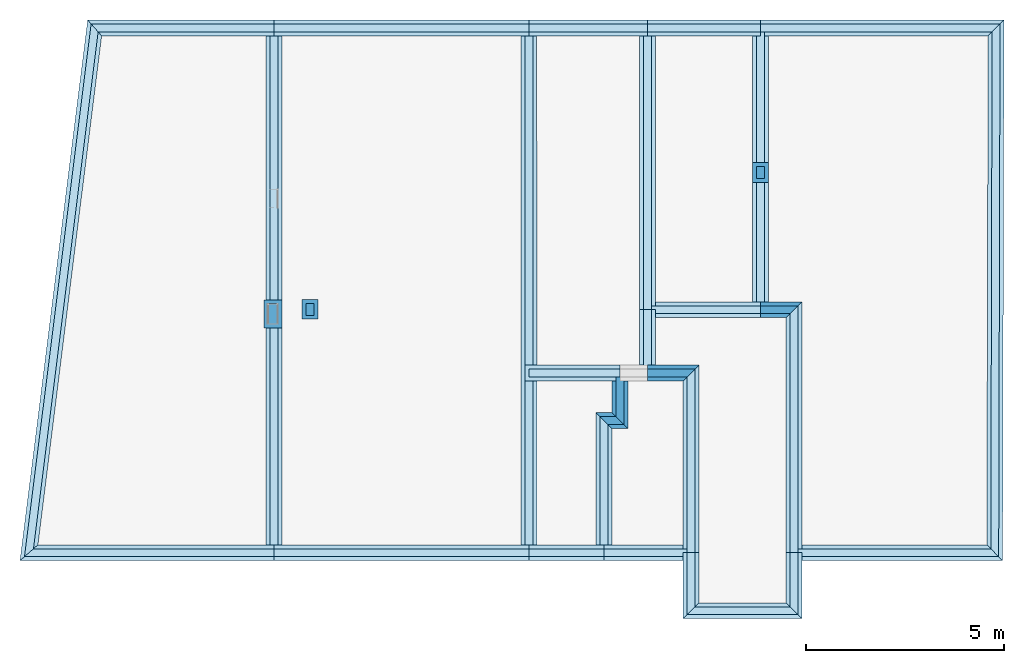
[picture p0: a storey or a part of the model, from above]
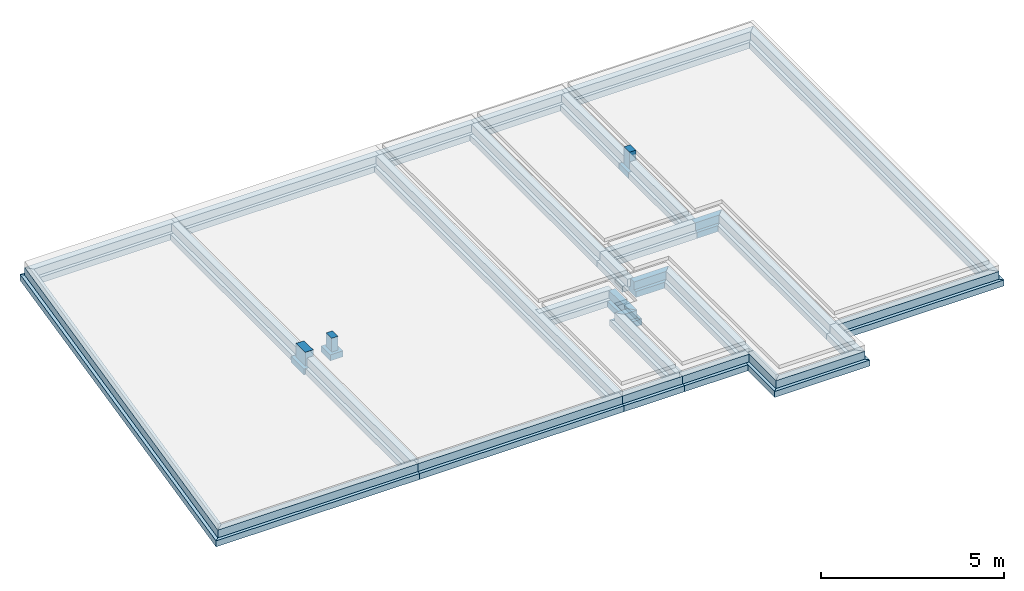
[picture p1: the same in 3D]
Properties of the parts of a building model (IFC2X3)

# File
Description: ISANGARD maison de santé et 9 logements, ViewDefinition [CoordinationView]
File name: G:\2023 Freyssinet\2023_MEC\00_Projet\23 24_04_ISANGARD\ISANGARD.IFC
Time: 2024-03-13T08:15:07
Author: Utilisateur par défaut
Written by: 2023-A
Made in: ATTIC+ Classic-Pack / Graphic-Pack Export_IFC 2023-A
Authorization: Personnes autorisées

# IfcProject, ISANGARD maison de santé et 9 logements
Description: ISANGARD maison de santé et 9 logements; Phase: EXE GROS OEUVRE ISANGARD

# IfcSite
RefLatitude: 0, 0, 0; RefLongitude: 0, 0, 0; RefElevation: 0 m

# IfcBuilding, Classeur ENS Ensemble
LongName: Classeur ENS Ensemble

# IfcBuildingStorey (5)
In: Classeur ENS Ensemble
Name | Description = LongName | Elevation (m)
000 Fondations | 000 Fondations | 0
001 RdC | 001 RdC | 0
002 R+1 | 002 R+1 | 3.3
003 R+2 | 003 R+2 | 6.03
004 Toiture Terrasse | 004 Toiture Terrasse | 8.73

# IfcBeam (184)
Type - PredefinedType: BEAM
Material: Default material
Name | In | Description | GrossVolume (m3) | NominalLength (m) | CrossSectionArea (m2) | OuterSurfaceArea (m2) | TotalSurfaceArea (m2)
3 x poutre fictive -32 | 000 Fondations | poutre fictive -32 | 0 | 0.15 | 0 | 0 | 0
7 x poutre fictive -32 | 000 Fondations | poutre fictive -32 | 0 | 0.1 | 0 | 0 | 0
poutre fictive -32 | 000 Fondations | poutre fictive -32 | 0 | 0.45 | 0 | 0 | 0
2 x poutre fictive -32 | 000 Fondations | poutre fictive -32 | 0 | 0.5 | 0 | 0 | 0
poutre fictive -32 | 000 Fondations | poutre fictive -32 | 0 | 0.0198567 | 0 | 0 | 0
poutre BA | 001 RdC | poutre BA | 0.390044 | 4.87555 | 0.08 | 1.95022 | 5.93066
poutre BA | 001 RdC | poutre BA | 0.00347491 | 0.0198567 | 0.175 | 0.0138997 | 0.212728
poutre BA | 001 RdC | poutre BA | 0.40425 | 2.31 | 0.175 | 1.617 | 4.494
poutre BA | 001 RdC | poutre BA | 0.22925 | 1.31 | 0.175 | 0.917 | 2.5765
poutre BA | 001 RdC | poutre BA | 0.28043 | 1.60246 | 0.175 | 1.12172 | 3.14951
poutre BA | 001 RdC | poutre BA | 0.133803 | 1.07043 | 0.125 | 0.535213 | 1.73064
poutre BA | 001 RdC | poutre BA | 0.22505 | 3.215 | 0.07 | 1.12525 | 3.6065
poutre BA | 001 RdC | poutre BA | 0.23835 | 3.405 | 0.07 | 1.19175 | 3.8155
poutre fictive | 001 RdC | poutre fictive | 0 | 0.075 | 0 | 0 | 0
poutre fictive | 001 RdC | poutre fictive | 0 | 0.125 | 0 | 0 | 0
poutre BA | 001 RdC | poutre BA | 0.21615 | 1.23514 | 0.175 | 0.8646 | 2.43427
poutre fictive | 001 RdC | poutre fictive | 0 | 0.63277 | 0 | 0 | 0
poutre fictive | 001 RdC | poutre fictive | 0 | 1.4652 | 0 | 0 | 0
poutre fictive | 001 RdC | poutre fictive | 0 | 5.06775 | 0 | 0 | 0
poutre fictive | 001 RdC | poutre fictive | 0 | 1.465 | 0 | 0 | 0
poutre fictive | 001 RdC | poutre fictive | 0 | 5.07148 | 0 | 0 | 0
poutre fictive | 001 RdC | poutre fictive | 0 | 0.1 | 0 | 0 | 0
poutre BA | 001 RdC | poutre BA | 0.004 | 0.1 | 0.04 | 0.02 | 0.12
poutre fictive | 001 RdC | poutre fictive | 0 | 0.124967 | 0 | 0 | 0
poutre fictive 285 | 001 RdC | poutre fictive 285 | 0 | 0.00999994 | 0 | 0 | 0
2 x poutre fictive 285 | 001 RdC | poutre fictive 285 | 0 | 0.12 | 0 | 0 | 0
Poutre auto | 001 RdC | Poutre auto | 0 | 5.88381 | 0 | 1.17676 | 2.35352
poutre BA | 001 RdC | poutre BA | 0.458125 | 3.665 | 0.125 | 1.8325 | 5.6225
poutre BA | 001 RdC | poutre BA | 0.0151187 | 0.120949 | 0.125 | 0.0604747 | 0.256424
poutre BA | 001 RdC | poutre BA | 0.140622 | 1.56247 | 0.09 | 0.70311 | 2.12121
poutre BA | 001 RdC | poutre BA | 0.009 | 0.1 | 0.09 | 0.045 | 0.22
poutre fictive 285 | 001 RdC | poutre fictive 285 | 0 | 0.1 | 0 | 0 | 0
poutre BA | 001 RdC | poutre BA | 0.0125 | 0.1 | 0.125 | 0.05 | 0.225
poutre BA | 001 RdC | poutre BA | 0.246601 | 2.74002 | 0.09 | 1.23301 | 3.65202
poutre BA | 001 RdC | poutre BA | 0.00000147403 | 0.249984 | 0.09 | 0.00000737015 | 0.190008
poutre BA | 001 RdC | poutre BA | 0.064 | 1.6 | 0.04 | 0.32 | 1.32
poutre fictive 310 | 001 RdC | poutre fictive 310 | 0 | 2.83619 | 0 | 0 | 0
poutre BA | 001 RdC | poutre BA | 0.048 | 1.2 | 0.04 | 0.24 | 1
poutre fictive 310 | 001 RdC | poutre fictive 310 | 0 | 4.34 | 0 | 0 | 0
Bande noyée 20 x 20 | 001 RdC | Bande noyée 20 x 20 | 0.0445201 | 1.113 | 0.04 | 0.222601 | 0.930403
poutre BA | 001 RdC | poutre BA | 0.68775 | 3.93 | 0.175 | 2.751 | 7.572
poutre BA | 001 RdC | poutre BA | 0.687751 | 3.93001 | 0.175 | 2.751 | 7.57217
poutre BA rive balcon | 001 RdC | poutre BA rive balcon | 0.105063 | 1.40084 | 0.075 | 0.700422 | 1.8961
poutre BA rive balcon | 001 RdC | poutre BA rive balcon | 0.00566888 | 0.0755851 | 0.075 | 0.0377926 | 0.182647
poutre BA rive balcon | 001 RdC | poutre BA rive balcon | 0.197344 | 2.63125 | 0.075 | 1.31563 | 3.49563
poutre BA rive balcon | 001 RdC | poutre BA rive balcon | 0.335239 | 4.46986 | 0.075 | 2.23493 | 5.88582
poutre fictive 290 | 001 RdC | poutre fictive 290 | 0 | 1.415 | 0 | 0 | 0
poutre fictive 290 | 001 RdC | poutre fictive 290 | 0 | 0.075 | 0 | 0 | 0
poutre fictive 290 | 001 RdC | poutre fictive 290 | 0 | 1.49 | 0 | 0 | 0
2 x poutre fictive 306 | 001 RdC | poutre fictive 306 | 0 | 0.075 | 0 | 0 | 0
3 x poutre fictive 306 | 001 RdC | poutre fictive 306 | 0 | 0.0755851 | 0 | 0 | 0
poutre fictive 306 | 001 RdC | poutre fictive 306 | 0 | 0.1 | 0 | 0 | 0
poutre BA rive balcon | 001 RdC | poutre BA rive balcon | 0.177301 | 2.36401 | 0.075 | 1.182 | 3.14821
poutre fictive 306 | 001 RdC | poutre fictive 306 | 0 | 4.82129 | 0 | 0 | 0
poutre fictive 306 | 001 RdC | poutre fictive 306 | 0 | 4.98587 | 0 | 0 | 0
poutre fictive 306 | 001 RdC | poutre fictive 306 | 0 | 1.315 | 0 | 0 | 0
poutre fictive 306 | 001 RdC | poutre fictive 306 | 0 | 1.32526 | 0 | 0 | 0
4 x poutre fictive 305 | 001 RdC | poutre fictive 305 | 0 | 0.1 | 0 | 0 | 0
2 x poutre fictive 305 | 001 RdC | poutre fictive 305 | 0 | 1.265 | 0 | 0 | 0
2 x poutre fictive 305 | 001 RdC | poutre fictive 305 | 0 | 0.2 | 0 | 0 | 0
poutre fictive 305 | 001 RdC | poutre fictive 305 | 0 | 0.360863 | 0 | 0 | 0
2 x poutre fictive 305 | 001 RdC | poutre fictive 305 | 0 | 6.74 | 0 | 0 | 0
poutre BA 20 x 40 | 001 RdC | poutre BA 20 x 40 | 1.18408e-10 | 0.2 | 0.08 | 5.92039e-10 | 0.32
poutre BA 20 x 40 | 001 RdC | poutre BA 20 x 40 | 0.192 | 2.4 | 0.08 | 0.96 | 3.12
poutre fictive 290 | 001 RdC | poutre fictive 290 | 0 | 0.2 | 0 | 0 | 0
poutre BA rive balcon | 001 RdC | poutre BA rive balcon | 0.122625 | 2.725 | 0.045 | 0.8175 | 2.4975
poutre BA rive balcon | 001 RdC | poutre BA rive balcon | 0.06705 | 1.49 | 0.045 | 0.447 | 1.386
poutre voile BA 20 cm | 002 R+1 | poutre voile BA 20 cm | 0.0337622 | 0.0566479 | 0.596 | 0.168811 | 0.956281
poutre voile BA 20 cm | 002 R+1 | poutre voile BA 20 cm | 0.94168 | 1.58 | 0.596 | 4.7084 | 10.0488
poutre voile BA 20 cm | 002 R+1 | poutre voile BA 20 cm | 0.75394 | 1.265 | 0.596 | 3.7697 | 9.8334
poutre voile BA 20 cm | 002 R+1 | poutre voile BA 20 cm | 3.44488 | 5.78 | 0.596 | 17.2244 | 38.2508
2 x poutre voile BA 20 cm | 002 R+1 | poutre voile BA 20 cm | 0.74129 | 1.265 | 0.586 | 3.70645 | 8.5049
poutre fictive 250 | 002 R+1 | poutre fictive 250 | 0 | 2.96294 | 0 | 0 | 0
poutre voile BA 20 cm | 002 R+1 | poutre voile BA 20 cm | 0.931731 | 1.56331 | 0.596 | 4.65865 | 10.5386
poutre voile BA 20 cm | 002 R+1 | poutre voile BA 20 cm | 1.54016 | 2.58416 | 0.596 | 7.70079 | 16.6588
poutre BA 20 x 48 | 002 R+1 | poutre BA 20 x 48 | 0.264359 | 2.75374 | 0.096 | 1.32179 | 3.84108
poutre BA 20 x 35 | 002 R+1 | poutre BA 20 x 35 | 0.319936 | 4.57052 | 0.07 | 1.59968 | 5.09757
poutre BA 20 x 35 | 002 R+1 | poutre BA 20 x 35 | 0.4963 | 7.09 | 0.07 | 2.4815 | 7.869
poutre BA 20 x 35 | 002 R+1 | poutre BA 20 x 35 | 0.014 | 0.2 | 0.07 | 0.07 | 0.29
2 x poutre fictive 250 | 002 R+1 | poutre fictive 250 | 0 | 1.5 | 0 | 0 | 0
2 x poutre fictive 250 | 002 R+1 | poutre fictive 250 | 0 | 1.70004 | 0 | 0 | 0
poutre BA 20 x 35 | 002 R+1 | poutre BA 20 x 35 | 0.253875 | 3.62678 | 0.07 | 1.26937 | 4.05946
poutre fictive 250 | 002 R+1 | poutre fictive 250 | 0 | 5.44 | 0 | 0 | 0
poutre fictive 250 | 002 R+1 | poutre fictive 250 | 0 | 3.94 | 0 | 0 | 0
poutre fictive 250 | 002 R+1 | poutre fictive 250 | 0 | 1.6 | 0 | 0 | 0
poutre fictive 250 | 002 R+1 | poutre fictive 250 | 0 | 4.78032 | 0 | 0 | 0
poutre fictive 250 | 002 R+1 | poutre fictive 250 | 0 | 2.86496 | 0 | 0 | 0
poutre fictive 250 | 002 R+1 | poutre fictive 250 | 0 | 2.84982 | 0 | 0 | 0
poutre BA 25 x 45 | 002 R+1 | poutre BA 25 x 45 | 0.211495 | 1.87996 | 0.1125 | 0.84598 | 2.74444
poutre fictive 250 | 002 R+1 | poutre fictive 250 | 0 | 2.00327 | 0 | 0 | 0
poutre BA 25 x 45 | 002 R+1 | poutre BA 25 x 45 | 0.0225 | 0.2 | 0.1125 | 0.09 | 0.3925
poutre BA 25 x 45 | 002 R+1 | poutre BA 25 x 45 | 0.385874 | 3.42999 | 0.1125 | 1.5435 | 4.91449
poutre BA 25 x 50 | 002 R+1 | poutre BA 25 x 50 | 0.131636 | 1.05309 | 0.125 | 0.526545 | 1.70464
poutre fictive 250 | 002 R+1 | poutre fictive 250 | 0 | 2.05496 | 0 | 0 | 0
poutre BA 25 x 50 | 002 R+1 | poutre BA 25 x 50 | 0.27441 | 3.92014 | 0.07 | 1.37205 | 4.38216
BN 23 | 002 R+1 | BN 23 | 0.0799049 | 1.73706 | 0.046 | 0.399525 | 1.53987
poutre fictive 250 | 002 R+1 | poutre fictive 250 | 0 | 2.5404 | 0 | 0 | 0
poutre fictive 250 | 002 R+1 | poutre fictive 250 | 0 | 2.25496 | 0 | 0 | 0
2 x poutre fictive 250 | 002 R+1 | poutre fictive 250 | 0 | 0.324552 | 0 | 0 | 0
poutre fictive 250 | 002 R+1 | poutre fictive 250 | 0 | 0.239541 | 0 | 0 | 0
poutre BA 25 x 45 | 002 R+1 | poutre BA 25 x 45 | 0.13613 | 1.21004 | 0.1125 | 0.544519 | 1.80656
poutre fictive 250 | 002 R+1 | poutre fictive 250 | 0 | 2.20308 | 0 | 0 | 0
poutre fictive 250 | 002 R+1 | poutre fictive 250 | 0 | 2.61028 | 0 | 0 | 0
BN 23 | 002 R+1 | BN 23 | 0.0571584 | 1.24257 | 0.046 | 0.285792 | 1.11461
poutre BA 25 x 50 | 002 R+1 | poutre BA 25 x 50 | 0.0249971 | 0.199977 | 0.125 | 0.0999883 | 0.424965
poutre BA 25 x 50 | 002 R+1 | poutre BA 25 x 50 | 0.454262 | 3.6341 | 0.125 | 1.81705 | 5.57615
poutre voile BA 20 cm | 002 R+1 | poutre voile BA 20 cm | 0.155142 | 0.260305 | 0.596 | 0.77571 | 2.25154
Poutre auto | 002 R+1 | Poutre auto | 0 | 5.3 | 0 | 1.219 | 2.438
BN 23 | 002 R+1 | BN 23 | 0.0716416 | 1.55743 | 0.046 | 0.358208 | 1.38539
poutre fictive 250 | 002 R+1 | poutre fictive 250 | 0 | 1.50225 | 0 | 0 | 0
poutre voile BA 20 cm | 002 R+1 | poutre voile BA 20 cm | 0.0260932 | 0.0437805 | 0.596 | 0.130466 | 0.874444
BN 23 | 002 R+1 | BN 23 | 0.0599095 | 1.30238 | 0.046 | 0.299547 | 1.16605
poutre voile BA 20 cm | 002 R+1 | poutre voile BA 20 cm | 0.15496 | 0.26 | 0.596 | 0.7748 | 1.9516
poutre BA 25 x 50 | 002 R+1 | poutre BA 25 x 50 | 0.522443 | 4.17955 | 0.125 | 2.08977 | 6.39432
poutre voile BA 20 cm | 002 R+1 | poutre voile BA 20 cm | 1.25912 | 2.11262 | 0.596 | 6.29561 | 13.6598
poutre fictive 250 | 002 R+1 | poutre fictive 250 | 0 | 0.0750014 | 0 | 0 | 0
poutre BA 25 x 50 | 002 R+1 | poutre BA 25 x 50 | 0.4675 | 3.74 | 0.125 | 1.87 | 5.735
PV BA 20 cm | 003 R+2 | PV BA 20 cm | 2.94167 | 5.01991 | 0.586 | 14.7083 | 32.0107
PV BA 20 cm | 003 R+2 | PV BA 20 cm | 0.175909 | 0.300186 | 0.586 | 0.879546 | 2.46517
PV BA 20 cm | 003 R+2 | PV BA 20 cm | 8.73199e-10 | 0.2 | 0.586 | 4.36599e-09 | 0.666
2 x PV BA 20 cm | 003 R+2 | PV BA 20 cm | 0.08204 | 0.14 | 0.586 | 0.4102 | 1.4624
PV BA 20 cm | 003 R+2 | PV BA 20 cm | 2.9024 | 4.95291 | 0.586 | 14.512 | 31.5912
PV BA 20 cm | 003 R+2 | PV BA 20 cm | 0.0586 | 0.1 | 0.586 | 0.293 | 1.212
poutre BA 20 x 45 | 003 R+2 | poutre BA 20 x 45 | 0.435604 | 4.84004 | 0.09 | 2.17802 | 6.38206
poutre BA 20 x 35 | 003 R+2 | poutre BA 20 x 35 | 0.273775 | 3.91107 | 0.07 | 1.36887 | 4.37217
BN 20 | 003 R+2 | BN 20 | 0.00124158 | 0.0310394 | 0.04 | 0.00620788 | 0.117875
BN 20 | 003 R+2 | BN 20 | 0.0680145 | 1.70036 | 0.04 | 0.340072 | 1.39418
BN 20 | 003 R+2 | BN 20 | 0.0512 | 1.28 | 0.04 | 0.256 | 1.064
BN 20 | 003 R+2 | BN 20 | 0.0488 | 1.22 | 0.04 | 0.244 | 1.016
poutre BA 20 x 40 | 003 R+2 | poutre BA 20 x 40 | 0.3552 | 4.44 | 0.08 | 1.776 | 5.408
2 x poutre BA 20 x 30 | 003 R+2 | poutre BA 20 x 30 | 0.2064 | 3.44 | 0.06 | 1.032 | 3.5
PV BA 20 cm | 003 R+2 | PV BA 20 cm | 0.00673267 | 0.0114892 | 0.586 | 0.0336634 | 0.883596
2 x poutre BA 20 x 30 | 003 R+2 | poutre BA 20 x 30 | 0.006 | 0.1 | 0.06 | 0.03 | 0.13
poutre BA 20 x 50 | 003 R+2 | poutre BA 20 x 50 | 0.276138 | 2.76138 | 0.1 | 1.38069 | 3.96593
PV BA 20 cm | 003 R+2 | PV BA 20 cm | 0.0518673 | 0.0885108 | 0.586 | 0.259337 | 0.914404
PV BA 20 cm | 003 R+2 | PV BA 20 cm | 0.966925 | 1.65004 | 0.586 | 4.83462 | 10.9153
3 x Poutre auto | 003 R+2 | Poutre auto | 0 | 1.2 | 0 | 0.24 | 0.48
Poutre auto | 003 R+2 | Poutre auto | 0 | 0.151589 | 0 | 0.0303178 | 0.0606357
4 x poutre fictive 250 | 003 R+2 | poutre fictive 250 | 0 | 0.1 | 0 | 0 | 0
PV BA 20 cm | 003 R+2 | PV BA 20 cm | 1.744 | 2.725 | 0.64 | 8.72 | 19.17
PV BA 20 cm | 003 R+2 | PV BA 20 cm | 1.776 | 2.775 | 0.64 | 8.88 | 19.51
2 x poutre fictive 250 | 003 R+2 | poutre fictive 250 | 0 | 0.14 | 0 | 0 | 0
2 x poutre fictive 250 | 003 R+2 | poutre fictive 250 | 0 | 0.0114892 | 0 | 0 | 0
2 x poutre fictive 250 | 003 R+2 | poutre fictive 250 | 0 | 2.81351 | 0 | 0 | 0
2 x poutre fictive 250 | 003 R+2 | poutre fictive 250 | 0 | 6.88 | 0 | 0 | 0
PV BA 20 cm | 003 R+2 | PV BA 20 cm | 2.25024 | 3.84 | 0.586 | 11.2512 | 24.6244
PV BA 20 cm | 003 R+2 | PV BA 20 cm | 0.036032 | 0.138512 | 0.586 | 0.18016 | 1.00172
Poutre auto | 003 R+2 | Poutre auto | 0 | 1.04841 | 0 | 0.209682 | 0.419364
poutre BA 20 x 30 | 003 R+2 | poutre BA 20 x 30 | 8.9406e-11 | 0.2 | 0.06 | 4.4703e-10 | 0.14

# IfcColumn (8)
Type - PredefinedType: COLUMN
Description: Poteau BA; Material: Default material
Name | In | NetVolume (m3) = GrossVolume (m3) | OuterSurfaceArea (m2) | CrossSectionArea (m2) | TotalSurfaceArea (m2) | NominalLength (m)
Poteau BA | 001 RdC | 0.39625 | 4.755 | 0.125 | 5.005 | 3.17
Poteau BA | 001 RdC | 0.1902 | 3.17 | 0.06 | 3.29 | 3.17
Poteau BA | 001 RdC | 0.2853 | 4.121 | 0.09 | 4.301 | 3.17
Poteau BA | 001 RdC | 0.183 | 3.05 | 0.06 | 3.17 | 3.05
Poteau BA | 002 R+1 | 0.125 | 2.25 | 0.05 | 2.35 | 2.5
Poteau BA | 002 R+1 | 0.1 | 2 | 0.04 | 2.08 | 2.5
2 x Poteau BA | 003 R+2 | 0.1 | 2 | 0.04 | 2.08 | 2.5

# IfcDoor (18)
Description: Porte
Name | In | OverallHeight (m) | OverallWidth (m)
4 x BL 100 x 215 | 001 RdC | 2.15 | 1
PE 93 x 212 | 001 RdC | 2.15 | 1
2 x PS 103 x 210 | 001 RdC | 2.1 | 1.03
PE 95 x 215 | 001 RdC | 2.15 | 0.95
2 x BL 170 x 215 | 001 RdC | 2.15 | 1.7
4 x PE 93 x 215 | 002 R+1 | 2.15 | 1
4 x PE 93 x 215 | 003 R+2 | 2.15 | 1

# IfcFooting (34)
In: 000 Fondations
Description: Semelle filante 40x20; Material: Default material
Name | PredefinedType
31 x Semelle filante 40x20 | STRIP_FOOTING
3 x Semelle filante 40x20 | PAD_FOOTING

# IfcOpeningElement (66)
Name | In | Description | NominalArea (m2)
5 x BL 300 x 115 | 001 RdC | BL 300 x 115 | 3.45
BL 200 x 115 | 001 RdC | BL 200 x 115 | 2.3
4 x BL 100 x 215 | 001 RdC | BL 100 x 215 | 2.15
PE 93 x 212 | 001 RdC | PE 93 x 212 | 2.15
4 x BL 90 x 115 | 001 RdC | BL 90 x 115 | 1.035
BL 90 x 195 | 001 RdC | BL 90 x 195 | 1.755
BL 300 x 215 | 001 RdC | BL 300 x 215 | 6.45
2 x PS 103 x 210 | 001 RdC | PS 103 x 210 | 2.163
PE 95 x 215 | 001 RdC | PE 95 x 215 | 2.0425
2 x BL 170 x 215 | 001 RdC | BL 170 x 215 | 3.655
10 x BL 90 x 165 | 002 R+1 | BL 90 x 165 | 1.485
3 x BL 300 x 215 | 002 R+1 | BL 300 x 215 | 6.45
4 x PE 93 x 215 | 002 R+1 | PE 93 x 215 | 2.15
BL 80 x 165 | 002 R+1 | BL 80 x 165 | 1.32
BL 200 x 215 | 002 R+1 | BL 200 x 215 | 4.3
BL 90 x 115 | 002 R+1 | BL 90 x 115 | 1.035
BL 100 x 215 | 002 R+1 | BL 100 x 215 | 2.15
12 x BL 90 x 165 | 003 R+2 | BL 90 x 165 | 1.485
BL 300 x 215 | 003 R+2 | BL 300 x 215 | 6
2 x BL 200 x 200 | 003 R+2 | BL 200 x 200 | 4
BL 100 x 200 | 003 R+2 | BL 100 x 200 | 2
BL 80 x 165 | 003 R+2 | BL 80 x 165 | 1.32
BL 200 x 215 | 003 R+2 | BL 200 x 215 | 4.3
4 x PE 93 x 215 | 003 R+2 | PE 93 x 215 | 2.15
BL 90 x 115 | 003 R+2 | BL 90 x 115 | 1.035

# IfcSlab (73)
Description: description dalle à préciser; PredefinedType: FLOOR; Material: Default material
Pset_SlabCommon - LoadBearing: yes
Name | In | Perimeter (m) | GrossArea (m2) = NetArea (m2) | GrossVolume (m3) = NetVolume (m3) | NominalWidth (m)
dallage porté 20 cm | 000 Fondations | 13.88 | 9.948 | 1.9896 | 0.2
dallage porté 20 cm | 000 Fondations | 20.1401 | 20.5771 | 4.11542 | 0.2
dallage porté 20 cm | 000 Fondations | 38.9973 | 75.976 | 15.1952 | 0.2
dallage porté 20 cm | 000 Fondations | 23.0099 | 22.4599 | 4.49197 | 0.2
dallage porté 20 cm | 000 Fondations | 32.9179 | 35.1779 | 7.03557 | 0.2
dallage porté 20 cm | 000 Fondations | 39.8021 | 86.6966 | 17.3393 | 0.2
dallage porté 20 cm | 000 Fondations | 37.9453 | 73.4938 | 14.6988 | 0.2
chape sur isolant 12 cm | 000 Fondations | 22.635 | 23.849 | 2.86188 | 0.12
chape sur isolant 12 cm | 000 Fondations | 19.14 | 18.338 | 2.20056 | 0.12
chape sur isolant 12 cm | 000 Fondations | 37.5968 | 69.7242 | 8.3669 | 0.12
chape sur isolant 12 cm | 000 Fondations | 21.7999 | 19.2819 | 2.31383 | 0.12
chape sur isolant 12 cm | 000 Fondations | 12.88 | 7.778 | 0.93336 | 0.12
chape sur isolant 12 cm | 000 Fondations | 12.68 | 8.2 | 0.984 | 0.12
hérisson 26 cm | 000 Fondations | 36.6391 | 67.3463 | 17.51 | 0.26
hérisson 26 cm | 000 Fondations | 38.6021 | 81.5081 | 21.1921 | 0.26
hérisson 26 cm | 000 Fondations | 22.615 | 23.7639 | 6.1786 | 0.26
hérisson 26 cm | 000 Fondations | 19.14 | 18.3378 | 4.76783 | 0.26
hérisson 26 cm | 000 Fondations | 37.5968 | 69.7242 | 18.1283 | 0.26
hérisson 26 cm | 000 Fondations | 12.88 | 7.778 | 2.02228 | 0.26
hérisson 26 cm | 000 Fondations | 12.68 | 8.2 | 2.132 | 0.26
hérisson 26 cm | 000 Fondations | 21.8099 | 19.3119 | 5.02111 | 0.26
Dalle BA 20 cm | 001 RdC | 13.0694 | 7.42749 | 1.4855 | 0.2
Dalle BA 25 cm | 001 RdC | 20.48 | 18.604 | 3.7208 | 0.2
Dalle BA 25 cm | 001 RdC | 13.48 | 9.508 | 1.9016 | 0.2
Dalle BA 25 cm | 001 RdC | 34.9826 | 60.4286 | 15.1072 | 0.25
Dalle BA 25 cm | 001 RdC | 51.7543 | 90.8216 | 22.7054 | 0.25
Dalle BA 20 cm | 001 RdC | 8.56147 | 4.05533 | 0.811065 | 0.2
Dalle BA 20 cm | 001 RdC | 23.4553 | 8.30274 | 1.66055 | 0.2
Dalle BA 20 cm | 001 RdC | 54.7424 | 86.1934 | 17.2387 | 0.2
Dalle BA 20 cm | 001 RdC | 14.9676 | 9.4141 | 1.88282 | 0.2
Dalle BA 20 cm | 001 RdC | 11.2724 | 7.94133 | 1.58827 | 0.2
Dalle BA 20 cm | 001 RdC | 13.28 | 8.198 | 1.6396 | 0.2
Dalle BA 25 cm | 001 RdC | 10.7935 | 5.50808 | 1.37702 | 0.25
Dalle BA 20 cm | 001 RdC | 12.169 | 6.65739 | 1.33148 | 0.2
Dalle BA 20 cm | 001 RdC | 12.4474 | 6.44821 | 1.22516 | 0.19
Dalle BA 20 cm | 001 RdC | 16.01 | 8.5261 | 1.70522 | 0.2
isolant sous face 15 | 001 RdC | 16.01 | 8.5261 | 1.27892 | 0.15
Dalle BA 20 cm | 001 RdC | 8.53 | 4.102 | 0.8204 | 0.2
Dalle BA 18 cm | 002 R+1 | 8.05916 | 3.50416 | 0.630749 | 0.18
Dalle BA 23 cm | 002 R+1 | 10.01 | 4.9486 | 1.13818 | 0.23
Dalle BA 23 cm | 002 R+1 | 9.61 | 4.6956 | 1.07999 | 0.23
Dalle BA 18 cm | 002 R+1 | 17.78 | 11.664 | 2.09952 | 0.18
Dalle BA 18 cm | 002 R+1 | 11.2491 | 6.88426 | 1.23917 | 0.18
Dalle BA 18 cm | 002 R+1 | 12.9581 | 7.79839 | 1.40371 | 0.18
Dalle BA 23 cm | 002 R+1 | 11.6362 | 5.37917 | 1.23721 | 0.23
Dalle BA 23 cm | 002 R+1 | 14.0399 | 10.974 | 2.52402 | 0.23
Dalle BA 23 cm | 002 R+1 | 8.11645 | 4.05287 | 0.932159 | 0.23
Dalle BA 23 cm | 002 R+1 | 15.7797 | 14.3635 | 3.30361 | 0.23
Dalle BA 23 cm | 002 R+1 | 9.65956 | 5.64253 | 1.29778 | 0.23
Dalle BA 23 cm | 002 R+1 | 23.66 | 33.1276 | 7.61935 | 0.23
Dalle BA 23 cm | 002 R+1 | 26.6831 | 39.1418 | 9.00261 | 0.23
Dalle BA 23 cm | 002 R+1 | 18.1 | 11.6506 | 2.67964 | 0.23
Dalle BA 23 cm | 002 R+1 | 13.9149 | 8.78436 | 2.0204 | 0.23
Dalle BA 23 cm | 002 R+1 | 18.96 | 19.9736 | 4.59393 | 0.23
Dalle BA 23 cm | 002 R+1 | 26.1539 | 35.1352 | 8.0811 | 0.23
Dalle BA 23 cm | 002 R+1 | 27.0246 | 36.8648 | 8.4789 | 0.23
Dalle BA 23 cm | 002 R+1 | 18.7817 | 20.456 | 4.70487 | 0.23
Dalle BA 23 cm | 002 R+1 | 5.96462 | 2.22342 | 0.511386 | 0.23
Dalle BA 23 cm | 002 R+1 | 17.7419 | 18.9944 | 4.36871 | 0.23
Dalle BA 20 cm | 003 R+2 | 26.4039 | 35.7436 | 7.14872 | 0.2
Dalle BA 20 cm | 003 R+2 | 9.00256 | 4.55645 | 0.911289 | 0.2
Dalle BA 20 cm | 003 R+2 | 40.9136 | 51.4003 | 10.2801 | 0.2
Dalle BA 20 cm | 003 R+2 | 26.2404 | 20.738 | 4.1476 | 0.2
Dalle BA 20 cm | 003 R+2 | 10.9 | 5.7226 | 1.14452 | 0.2
Dalle BA 20 cm | 003 R+2 | 5.8 | 2.1016 | 0.42032 | 0.2
Dalle BA 20 cm | 003 R+2 | 5.16 | 1.315 | 0.263 | 0.2
Dalle BA 20 cm | 003 R+2 | 23.7727 | 36.582 | 7.31641 | 0.2
Dalle BA 20 cm | 003 R+2 | 20.5861 | 26.4779 | 5.29558 | 0.2
Dalle BA 20 cm | 003 R+2 | 14.8613 | 12.5356 | 2.50712 | 0.2
Dalle BA 20 cm | 003 R+2 | 28.4824 | 40.4191 | 8.08383 | 0.2
Dalle BA 20 cm | 003 R+2 | 24.9446 | 36.009 | 7.20179 | 0.2
Dalle BA 20 cm | 003 R+2 | 19.867 | 21.0082 | 4.20163 | 0.2
Étanchéité sur isolant | 004 Toiture Terrasse | 80.535 | 281.75 | 45.08 | 0.16

# IfcWall (175)
Type - PredefinedType: STANDARD
Pset_WallCommon - LoadBearing: yes
Name | In | Description | Material | NominalLength (m) | GrossSideArea (m2) | GrossSideAreaRight (m2) | NetSideAreaRight (m2) | GrossFootprintArea (m2) | NominalHeight (m) | GrossSideAreaLeft (m2) | GrossVolume (m3) | NominalWidth (m) | NetFootprintArea (m2) | NetSideAreaLeft (m2) | NetVolume (m3) | NetSideArea (m2)
voile BA 20 cm | 001 RdC | voile BA 20 cm | voile BA 20 cm 0.2 m | 10.9696 | 34.7736 | 34.1768 | 24.1268 | 2.19392 | 3.17 | 35.0534 | 6.95472 | 0.2 | 1.79392 | 25.0034 | 4.94472 | 24.7236
voile BA 20 cm | 001 RdC | voile BA 20 cm | voile BA 20 cm 0.2 m | 1.4996 | 4.82872 | 5.1499 | 5.1499 | 0.29992 | 3.22 | 4.50753 | 0.965743 | 0.2 | 0.29992 | 4.50753 | 0.965743 | 4.82872
voile BA 20 cm | 001 RdC | voile BA 20 cm | voile BA 20 cm 0.2 m | 0.2 | 3.72525e-09 | 3.72525e-09 | 3.72525e-09 | 0.04 | 2.5 | 3.72525e-09 | 7.45051e-10 | 0.2 | 0.04 | 3.72525e-09 | 7.45051e-10 | 3.72525e-09
voile BA 20 cm | 001 RdC | voile BA 20 cm | voile BA 20 cm 0.2 m | 1.465 | 4.7173 | 4.7173 | 4.7173 | 0.293 | 3.22 | 4.3953 | 0.94346 | 0.2 | 0.293 | 4.3953 | 0.94346 | 4.7173
voile BA 20 cm | 001 RdC | voile BA 20 cm | voile BA 20 cm 0.2 m | 2.6 | 8.372 | 9.016 | 9.016 | 0.52 | 3.22 | 7.728 | 1.6744 | 0.2 | 0.52 | 7.728 | 1.6744 | 8.372
voile BA 20 cm | 001 RdC | voile BA 20 cm | voile BA 20 cm 0.2 m | 1.465 | 4.7173 | 4.3953 | 2.2323 | 0.293 | 3.22 | 5.0393 | 0.94346 | 0.2 | 0.087 | 2.8763 | 0.51086 | 2.5543
voile BA 20 cm | 001 RdC | voile BA 20 cm | voile BA 20 cm 0.2 m | 1.5 | 4.83 | 4.508 | 4.508 | 0.3 | 3.22 | 4.83 | 0.966 | 0.2 | 0.3 | 4.83 | 0.966 | 4.83
voile BA 20 cm | 001 RdC | voile BA 20 cm | voile BA 20 cm 0.2 m | 2.85 | 9.177 | 8.855 | 7.82 | 0.57 | 3.22 | 9.177 | 1.8354 | 0.2 | 0.57 | 8.142 | 1.6284 | 8.142
voile BA 20 cm | 001 RdC | voile BA 20 cm | voile BA 20 cm 0.2 m | 1.4996 | 4.8287 | 4.5067 | 4.5067 | 0.299919 | 3.22 | 4.8287 | 0.96574 | 0.2 | 0.299919 | 4.8287 | 0.96574 | 4.8287
voile BA 20 cm | 001 RdC | voile BA 20 cm | voile BA 20 cm 0.2 m | 2.75 | 8.855 | 8.855 | 8.855 | 0.55 | 3.22 | 8.855 | 1.771 | 0.2 | 0.55 | 8.855 | 1.771 | 8.855
voile BA 20 cm | 001 RdC | voile BA 20 cm | voile BA 20 cm 0.2 m | 1.23619 | 3.98052 | 3.65852 | 1.62485 | 0.247238 | 3.22 | 3.98052 | 0.796105 | 0.2 | 0.0580587 | 1.94685 | 0.38937 | 1.94685
voile BA 20 cm | 001 RdC | voile BA 20 cm | voile BA 20 cm 0.2 m | 1.1 | 3.542 | 3.864 | 3.864 | 0.22 | 3.22 | 3.22 | 0.7084 | 0.2 | 0.22 | 3.22 | 0.7084 | 3.542
voile BA 20 cm | 001 RdC | voile BA 20 cm | voile BA 20 cm 0.2 m | 0.4 | 1.288 | 1.288 | 1.288 | 0.08 | 3.22 | 1.288 | 0.2576 | 0.2 | 0.08 | 1.288 | 0.2576 | 1.288
voile BA 20 cm | 001 RdC | voile BA 20 cm | voile BA 20 cm 0.2 m | 3.04 | 9.7888 | 9.4668 | 9.4668 | 0.608 | 3.22 | 10.1108 | 1.95776 | 0.2 | 0.608 | 10.1108 | 1.95776 | 9.7888
voile BA 20 cm | 001 RdC | voile BA 20 cm | voile BA 20 cm 0.2 m | 4.34 | 13.9748 | 14.2968 | 14.2968 | 0.868 | 3.22 | 13.3308 | 2.79496 | 0.2 | 0.868 | 13.3308 | 2.79496 | 13.9748
2 x voile BA 20 cm | 001 RdC | voile BA 20 cm | voile BA 20 cm 0.2 m | 0.2 | 4.65031e-09 | 4.65031e-09 | 4.65031e-09 | 0.04 | 3.1 | 4.65031e-09 | 9.30061e-10 | 0.2 | 0.04 | 4.65031e-09 | 9.30061e-10 | 4.65031e-09
voile BA 20 cm | 001 RdC | voile BA 20 cm | voile BA 20 cm 0.2 m | 0.2 | 0.634 | 0.634 | 0.634 | 0.04 | 3.17 | 0.317 | 0.1268 | 0.2 | 0.04 | 0.317 | 0.1268 | 0.634
voile BA 20 cm | 001 RdC | voile BA 20 cm | voile BA 20 cm 0.2 m | 1.3 | 4.186 | 3.864 | 3.864 | 0.26 | 3.22 | 4.186 | 0.8372 | 0.2 | 0.26 | 4.186 | 0.8372 | 4.186
voile BA 20 cm | 001 RdC | voile BA 20 cm | voile BA 20 cm 0.2 m | 5.05917 | 16.0376 | 16.3967 | 12.4717 | 1.01183 | 3.17 | 15.6784 | 3.20751 | 0.2 | 0.967648 | 11.7534 | 2.42251 | 12.1126
voile BA 20 cm | 001 RdC | voile BA 20 cm | voile BA 20 cm 0.2 m | 11.56 | 37.2233 | 37.5461 | 37.5461 | 2.31201 | 3.22 | 36.9005 | 7.44466 | 0.2 | 2.31201 | 36.9005 | 7.44466 | 37.2233
voile BA 20 cm | 001 RdC | voile BA 20 cm | voile BA 20 cm 0.2 m | 4.44 | 14.2968 | 14.6188 | 14.6188 | 0.888 | 3.22 | 13.9748 | 2.85936 | 0.2 | 0.888 | 13.9748 | 2.85936 | 14.2968
voile BA 20 cm | 001 RdC | voile BA 20 cm | voile BA 20 cm 0.2 m | 5.625 | 17.8312 | 17.8312 | 17.8312 | 1.125 | 3.17 | 17.8312 | 3.56625 | 0.2 | 1.125 | 17.8312 | 3.56625 | 17.8312
voile BA 20 cm | 001 RdC | voile BA 20 cm | voile BA 20 cm 0.2 m | 1.21137 | 3.84003 | 3.84003 | 3.84003 | 0.242273 | 3.17 | 3.84003 | 0.768006 | 0.2 | 0.242273 | 3.84003 | 0.768006 | 3.84003
voile BA 20 cm | 001 RdC | voile BA 20 cm | voile BA 20 cm 0.2 m | 4.44944 | 14.1047 | 13.8249 | 8.4132 | 0.889889 | 3.17 | 14.3845 | 2.82095 | 0.2 | 0.707401 | 8.97279 | 1.7386 | 8.69299
voile BA 20 cm | 001 RdC | voile BA 20 cm | voile BA 20 cm 0.2 m | 0.85 | 2.737 | 2.415 | 2.415 | 0.17 | 3.22 | 3.059 | 0.5474 | 0.2 | 0.17 | 3.059 | 0.5474 | 2.737
voile BA 20 cm | 001 RdC | voile BA 20 cm | voile BA 20 cm 0.2 m | 5.95547 | 19.1766 | 18.8538 | 16.7838 | 1.19109 | 3.22 | 19.4994 | 3.83532 | 0.2 | 1.19109 | 17.4294 | 3.42132 | 17.1066
voile BA 20 cm | 001 RdC | voile BA 20 cm | voile BA 20 cm 0.2 m | 4.97173 | 16.009 | 16.3302 | 9.88016 | 0.994347 | 3.22 | 15.6878 | 3.2018 | 0.2 | 0.994347 | 9.2378 | 1.9118 | 9.55898
voile BA 20 cm | 001 RdC | voile BA 20 cm | voile BA 20 cm 0.2 m | 0.126175 | 0.399973 | 0.399973 | 0.211718 | 0.0252349 | 3.17 | 0.399973 | 0.0799947 | 0.2 | 0.00772279 | 0.211718 | 0.0423436 | 0.211718
voile BA 20 cm | 001 RdC | voile BA 20 cm | voile BA 20 cm 0.2 m | 2.76118 | 8.2007 | 8.2007 | 7.21768 | 0.552235 | 2.97 | 8.2007 | 1.64014 | 0.2 | 0.552235 | 7.21768 | 1.44354 | 7.21768
voile BA 20 cm | 001 RdC | voile BA 20 cm | voile BA 20 cm 0.2 m | 1.7 | 5.474 | 5.152 | 3.397 | 0.34 | 3.22 | 5.474 | 1.0948 | 0.2 | 0.34 | 3.719 | 0.7438 | 3.719
voile BA 20 cm | 001 RdC | voile BA 20 cm | voile BA 20 cm 0.2 m | 5.92587 | 18.785 | 18.4259 | 14.9759 | 1.18517 | 3.17 | 19.1442 | 3.757 | 0.2 | 1.18517 | 15.6942 | 3.067 | 15.335
voile BA 20 cm | 001 RdC | voile BA 20 cm | voile BA 20 cm 0.2 m | 0.10078 | 0.319473 | 0.319473 | 0.267486 | 0.020156 | 3.17 | 0.319473 | 0.0638946 | 0.2 | 0.020156 | 0.267486 | 0.0534971 | 0.267486
voile BA 20 cm | 001 RdC | voile BA 20 cm | voile BA 20 cm 0.2 m | 0.200404 | 0.645301 | 0.645301 | 0.645301 | 0.0400808 | 3.22 | 0.645301 | 0.12906 | 0.2 | 0.0400808 | 0.645301 | 0.12906 | 0.645301
voile BA 20 cm | 001 RdC | voile BA 20 cm | voile BA 20 cm 0.2 m | 0.200403 | 0.645299 | 0.645299 | 0.645299 | 0.0400807 | 3.22 | 0.645299 | 0.12906 | 0.2 | 0.0400807 | 0.645299 | 0.12906 | 0.645299
voile BA 20 cm | 001 RdC | voile BA 20 cm | voile BA 20 cm 0.2 m | 4.34 | 13.7578 | 13.1238 | 13.1238 | 0.868 | 3.17 | 13.7578 | 2.75156 | 0.2 | 0.868 | 13.7578 | 2.75156 | 13.7578
voile BA 20 cm | 001 RdC | voile BA 20 cm | voile BA 20 cm 0.2 m | 1.62482 | 5.15069 | 4.83369 | 4.83369 | 0.324964 | 3.17 | 5.15069 | 1.03014 | 0.2 | 0.324964 | 5.15069 | 1.03014 | 5.15069
voile BA 20 cm | 001 RdC | voile BA 20 cm | voile BA 20 cm 0.2 m | 2.1 | 6.762 | 6.762 | 4.599 | 0.42 | 3.22 | 6.44 | 1.3524 | 0.2 | 0.214 | 4.277 | 0.9198 | 4.599
voile BA 20 cm | 001 RdC | voile BA 20 cm | voile BA 20 cm 0.2 m | 0.158812 | 0.503435 | 0.503435 | 0.503435 | 0.0317625 | 3.17 | 0.503435 | 0.100687 | 0.2 | 0.0317625 | 0.503435 | 0.100687 | 0.503435
voile BA 20 cm | 001 RdC | voile BA 20 cm | voile BA 20 cm 0.2 m | 5.78381 | 18.6239 | 18.6239 | 18.615 | 1.15676 | 3.22 | 18.6239 | 3.72478 | 0.2 | 1.15594 | 18.615 | 3.72301 | 18.615
voile BA 20 cm | 001 RdC | voile BA 20 cm | voile BA 20 cm 0.2 m | 1.1 | 3.542 | 3.22 | 3.22 | 0.22 | 3.22 | 3.542 | 0.7084 | 0.2 | 0.22 | 3.542 | 0.7084 | 3.542
voile BA 20 cm | 001 RdC | voile BA 20 cm | voile BA 20 cm 0.2 m | 0.7 | 2.254 | 1.932 | 1.932 | 0.14 | 3.22 | 1.932 | 0.4508 | 0.2 | 0.14 | 1.932 | 0.4508 | 2.254
voile BA 20 cm | 001 RdC | voile BA 20 cm | voile BA 20 cm 0.2 m | 2.2 | 7.084 | 6.762 | 3.10944 | 0.44 | 3.22 | 7.084 | 1.4168 | 0.2 | 0.100227 | 3.43144 | 0.686287 | 3.43144
voile BA 20 cm | 001 RdC | voile BA 20 cm | voile BA 20 cm 0.2 m | 1.8 | 5.796 | 5.796 | 2.14666 | 0.36 | 3.22 | 5.474 | 1.1592 | 0.2 | 0.0205266 | 1.82466 | 0.429332 | 2.14666
voile BA 20 cm | 001 RdC | voile BA 20 cm | voile BA 20 cm 0.2 m | 0.469082 | 1.48699 | 1.80399 | 1.80399 | 0.0938163 | 3.17 | 1.16999 | 0.297398 | 0.2 | 0.0938163 | 1.16999 | 0.297398 | 1.48699
voile BA 20 cm | 001 RdC | voile BA 20 cm | voile BA 20 cm 0.2 m | 0.2 | 4.76591e-09 | 4.76591e-09 | 4.76591e-09 | 0.04 | 3.22 | 4.76591e-09 | 9.53183e-10 | 0.2 | 0.04 | 4.76591e-09 | 9.53183e-10 | 4.76591e-09
voile BA 20 cm | 001 RdC | voile BA 20 cm | voile BA 20 cm 0.2 m | 0.469625 | 1.48871 | 1.48871 | 0.479017 | 0.0939249 | 3.17 | 1.48871 | 0.297742 | 0.2 | 0 | 0.479017 | 0.0958034 | 0.479017
voile BA 20 cm | 001 RdC | voile BA 20 cm | voile BA 20 cm 0.2 m | 6.27038 | 19.8771 | 19.8771 | 14.3852 | 1.25408 | 3.17 | 19.8771 | 3.97542 | 0.2 | 1.06414 | 14.3852 | 2.87705 | 14.3852
voile BA 20 cm | 001 RdC | voile BA 20 cm | voile BA 20 cm 0.2 m | 0.360918 | 1.14411 | 1.14411 | 0.370638 | 0.0721837 | 3.17 | 1.14411 | 0.228822 | 0.2 | 0.00023269 | 0.370638 | 0.0741276 | 0.370638
voile BA 20 cm | 001 RdC | voile BA 20 cm | voile BA 20 cm 0.2 m | 0.2 | 0.644 | 0.644 | 0.644 | 0.04 | 3.22 | 0.322 | 0.1288 | 0.2 | 0.04 | 0.322 | 0.1288 | 0.644
mur BBM 20 cm | 002 R+1 | mur BBM 20 cm | mur BBM 20 cm 0.2 m | 4.52959 | 11.324 | 11.1033 | 8.13331 | 0.905918 | 2.5 | 11.5446 | 2.26479 | 0.2 | 0.905918 | 8.57463 | 1.67079 | 8.35397
mur BBM 20 cm | 002 R+1 | mur BBM 20 cm | mur BBM 20 cm 0.2 m | 2.84981 | 7.12453 | 6.87453 | 5.38953 | 0.569962 | 2.5 | 7.12453 | 1.42491 | 0.2 | 0.569962 | 5.63953 | 1.12791 | 5.63953
mur BBM 20 cm | 002 R+1 | mur BBM 20 cm | mur BBM 20 cm 0.2 m | 1.5 | 3.75 | 3.75 | 3.75 | 0.3 | 2.5 | 3.5 | 0.75 | 0.2 | 0.3 | 3.5 | 0.75 | 3.75
voile BA 20 cm | 002 R+1 | voile BA 20 cm | voile BA 20 cm 0.2 m | 1.13619 | 2.84047 | 2.84047 | 0.690469 | 0.227238 | 2.5 | 2.84047 | 0.568094 | 0.2 | 0.0272375 | 0.690469 | 0.138094 | 0.690469
mur BBM 20 cm | 002 R+1 | mur BBM 20 cm | mur BBM 20 cm 0.2 m | 2.2 | 5.5 | 5.5 | 2.48454 | 0.44 | 2.5 | 5.5 | 1.1 | 0.2 | 0.44 | 2.48454 | 0.496908 | 2.48454
mur BBM 20 cm | 002 R+1 | mur BBM 20 cm | mur BBM 20 cm 0.2 m | 1.3 | 3.25 | 3 | 3 | 0.26 | 2.5 | 3.25 | 0.65 | 0.2 | 0.26 | 3.25 | 0.65 | 3.25
mur BBM 20 cm | 002 R+1 | mur BBM 20 cm | mur BBM 20 cm 0.2 m | 4.85917 | 12.1479 | 12.0532 | 5.60323 | 0.971834 | 2.5 | 11.8647 | 2.42958 | 0.2 | 0.971834 | 5.41468 | 1.13958 | 5.69792
mur BBM 20 cm | 002 R+1 | mur BBM 20 cm | mur BBM 20 cm 0.2 m | 1.70005 | 4.25012 | 4.49949 | 4.49949 | 0.34001 | 2.5 | 4.00076 | 0.850024 | 0.2 | 0.34001 | 4.00076 | 0.850024 | 4.25012
voile BA 20 cm | 002 R+1 | voile BA 20 cm | voile BA 20 cm 0.2 m | 4.365 | 10.9125 | 10.9125 | 10.9125 | 0.873 | 2.5 | 10.9125 | 2.1825 | 0.2 | 0.873 | 10.9125 | 2.1825 | 10.9125
mur BBM 20 cm | 002 R+1 | mur BBM 20 cm | mur BBM 20 cm 0.2 m | 5.95547 | 14.8887 | 14.638 | 11.668 | 1.19109 | 2.5 | 15.1393 | 2.97774 | 0.2 | 1.19109 | 12.1693 | 2.38374 | 11.9187
mur BBM 20 cm | 002 R+1 | mur BBM 20 cm | mur BBM 20 cm 0.2 m | 1.15309 | 2.88273 | 2.63273 | 2.63273 | 0.230618 | 2.5 | 2.63273 | 0.576545 | 0.2 | 0.230618 | 2.63273 | 0.576545 | 2.88273
voile BA 20 cm | 002 R+1 | voile BA 20 cm | voile BA 20 cm 0.2 m | 0.6 | 1.5 | 1.75 | 1.75 | 0.12 | 2.5 | 1.25 | 0.3 | 0.2 | 0.12 | 1.25 | 0.3 | 1.5
voile BA 20 cm | 002 R+1 | voile BA 20 cm | voile BA 20 cm 0.2 m | 0.583812 | 1.45953 | 1.45953 | 1.45953 | 0.116762 | 2.5 | 1.45953 | 0.291906 | 0.2 | 0.116762 | 1.45953 | 0.291906 | 1.45953
mur BBM 20 cm | 002 R+1 | mur BBM 20 cm | mur BBM 20 cm 0.2 m | 0.0425733 | 0.106433 | 0.106433 | 0.106433 | 0.00851465 | 2.5 | 0.106433 | 0.0212866 | 0.2 | 0.00851465 | 0.106433 | 0.0212866 | 0.106433
mur BBM 20 cm | 002 R+1 | mur BBM 20 cm | mur BBM 20 cm 0.2 m | 1.5128 | 3.78199 | 3.49875 | 3.49875 | 0.302559 | 2.5 | 4.06523 | 0.756398 | 0.2 | 0.302559 | 4.06523 | 0.756398 | 3.78199
mur BBM 20 cm | 002 R+1 | mur BBM 20 cm | mur BBM 20 cm 0.2 m | 3.34 | 8.35 | 8.35 | 8.35 | 0.668 | 2.5 | 8.35 | 1.67 | 0.2 | 0.668 | 8.35 | 1.67 | 8.35
mur BBM 20 cm | 002 R+1 | mur BBM 20 cm | mur BBM 20 cm 0.2 m | 1.9 | 4.75 | 4.75 | 2.6 | 0.38 | 2.5 | 4.75 | 0.95 | 0.2 | 0.38 | 2.6 | 0.52 | 2.6
4 x mur BBM 20 cm | 002 R+1 | mur BBM 20 cm | mur BBM 20 cm 0.2 m | 0.1 | 0.25 | 0.25 | 0.25 | 0.02 | 2.5 | 0.25 | 0.05 | 0.2 | 0.02 | 0.25 | 0.05 | 0.25
mur BBM 20 cm | 002 R+1 | mur BBM 20 cm | mur BBM 20 cm 0.2 m | 0.2 | 0.5 | 0.25 | 0.25 | 0.04 | 2.5 | 0.5 | 0.1 | 0.2 | 0.04 | 0.5 | 0.1 | 0.5
voile BA 20 cm | 002 R+1 | voile BA 20 cm | voile BA 20 cm 0.2 m | 1.50224 | 3.75559 | 3.50559 | 3.50559 | 0.300448 | 2.5 | 3.75559 | 0.751119 | 0.2 | 0.300448 | 3.75559 | 0.751119 | 3.75559
voile BA 20 cm | 002 R+1 | voile BA 20 cm | voile BA 20 cm 0.2 m | 0.4 | 1 | 1.25 | 1.25 | 0.08 | 2.5 | 0.75 | 0.2 | 0.2 | 0.08 | 0.75 | 0.2 | 1
mur BBM 20 cm | 002 R+1 | mur BBM 20 cm | mur BBM 20 cm 0.2 m | 0.00969476 | 0.0242369 | 0.0242369 | 0.0242369 | 0.00193895 | 2.5 | 0.0242369 | 0.00484738 | 0.2 | 0.00193895 | 0.0242369 | 0.00484738 | 0.0242369
voile BA 20 cm | 002 R+1 | voile BA 20 cm | voile BA 20 cm 0.2 m | 2.35 | 5.875 | 5.625 | 5.625 | 0.47 | 2.5 | 5.875 | 1.175 | 0.2 | 0.47 | 5.875 | 1.175 | 5.875
voile BA 20 cm | 002 R+1 | voile BA 20 cm | voile BA 20 cm 0.2 m | 1.05 | 2.625 | 2.625 | 0.475 | 0.21 | 2.5 | 2.625 | 0.525 | 0.2 | 0.01 | 0.475 | 0.095 | 0.475
mur BBM 15 cm allégés | 002 R+1 | mur BBM 15 cm allégés | mur BBM 15 cm allégés 0.15 m | 1.40084 | 1.47089 | 1.39152 | 1.39152 | 0.210127 | 1.05 | 1.56011 | 0.220633 | 0.15 | 0.210127 | 1.56011 | 0.220633 | 1.47089
mur BBM 15 cm allégés | 002 R+1 | mur BBM 15 cm allégés | mur BBM 15 cm allégés 0.15 m | 2.43959 | 2.56157 | 2.6508 | 2.6508 | 0.365939 | 1.05 | 2.47235 | 0.384236 | 0.15 | 0.365939 | 2.47235 | 0.384236 | 2.56157
mur BBM 15 cm allégés | 002 R+1 | mur BBM 15 cm allégés | mur BBM 15 cm allégés 0.15 m | 2.8 | 2.94 | 2.94 | 2.94 | 0.42 | 1.05 | 2.94 | 0.441 | 0.15 | 0.42 | 2.94 | 0.441 | 2.94
mur BBM 15 cm allégés | 002 R+1 | mur BBM 15 cm allégés | mur BBM 15 cm allégés 0.15 m | 2.24688 | 2.35922 | 2.43777 | 2.43777 | 0.337031 | 1.05 | 2.28067 | 0.353883 | 0.15 | 0.337031 | 2.28067 | 0.353883 | 2.35922
mur BBM 15 cm allégés | 002 R+1 | mur BBM 15 cm allégés | mur BBM 15 cm allégés 0.15 m | 2.89001 | 3.03451 | 3.11306 | 3.11306 | 0.433501 | 1.05 | 2.95576 | 0.455176 | 0.15 | 0.433501 | 2.95576 | 0.455176 | 3.03451
mur BBM 20 cm | 002 R+1 | mur BBM 20 cm | mur BBM 20 cm 0.2 m | 2.6 | 6.5 | 6.75 | 3.31546 | 0.52 | 2.5 | 6.25 | 1.3 | 0.2 | 0.52 | 2.81546 | 0.613091 | 3.06546
mur BBM 20 cm | 002 R+1 | mur BBM 20 cm | mur BBM 20 cm 0.2 m | 0.10078 | 0.25195 | 0.53519 | 0.53519 | 0.020156 | 2.5 | 0.0312892 | 0.0503901 | 0.2 | 0.020156 | 0.0312892 | 0.0503901 | 0.25195
mur BBM 20 cm | 002 R+1 | mur BBM 20 cm | mur BBM 20 cm 0.2 m | 4.47464 | 11.1866 | 10.6827 | 10.6827 | 0.894928 | 2.5 | 11.6905 | 2.23732 | 0.2 | 0.894928 | 11.6905 | 2.23732 | 11.1866
mur BBM 20 cm | 002 R+1 | mur BBM 20 cm | mur BBM 20 cm 0.2 m | 2.94 | 7.35 | 7.10007 | 2.80007 | 0.588 | 2.5 | 7.59993 | 1.47 | 0.2 | 0.588 | 3.29993 | 0.61 | 3.05
mur BBM 20 cm | 002 R+1 | mur BBM 20 cm | mur BBM 20 cm 0.2 m | 2.85453 | 2.68326 | 2.68326 | 2.68326 | 0.570906 | 0.94 | 2.68326 | 0.536652 | 0.2 | 0.570906 | 2.68326 | 0.536652 | 2.68326
voile BA 20 cm | 002 R+1 | voile BA 20 cm | voile BA 20 cm 0.2 m | 2.84982 | 7.12456 | 7.12456 | 7.12456 | 0.569965 | 2.5 | 6.87456 | 1.42491 | 0.2 | 0.569965 | 6.87456 | 1.42491 | 7.12456
voile BA 20 cm | 002 R+1 | voile BA 20 cm | voile BA 20 cm 0.2 m | 3 | 7.5 | 7.25 | 5.1 | 0.6 | 2.5 | 7.25 | 1.5 | 0.2 | 0.4 | 5.1 | 1.07 | 5.35
voile BA 20 cm | 002 R+1 | voile BA 20 cm | voile BA 20 cm 0.2 m | 0.6 | 1.5 | 1.25 | 1.25 | 0.12 | 2.5 | 1.75 | 0.3 | 0.2 | 0.12 | 1.75 | 0.3 | 1.5
voile BA 20 cm | 002 R+1 | voile BA 20 cm | voile BA 20 cm 0.2 m | 1.68 | 4.2 | 3.7 | 3.7 | 0.336 | 2.5 | 4.2 | 0.84 | 0.2 | 0.336 | 4.2 | 0.84 | 4.2
voile BA 20 cm | 002 R+1 | voile BA 20 cm | voile BA 20 cm 0.2 m | 0.99 | 2.475 | 2.725 | 2.725 | 0.198 | 2.5 | 2.225 | 0.495 | 0.2 | 0.198 | 2.225 | 0.495 | 2.475
mur BBM 20 cm | 002 R+1 | mur BBM 20 cm | mur BBM 20 cm 0.2 m | 1.19448 | 2.98619 | 2.73626 | 1.41626 | 0.238895 | 2.5 | 3.23611 | 0.597238 | 0.2 | 0.238895 | 1.91611 | 0.333238 | 1.66619
mur BBM 20 cm | 002 R+1 | mur BBM 20 cm | mur BBM 20 cm 0.2 m | 0.129368 | 0.323419 | 0.323419 | 0.323419 | 0.0258735 | 2.5 | 0.323419 | 0.0646838 | 0.2 | 0.0258735 | 0.323419 | 0.0646838 | 0.323419
mur BBM 20 cm | 002 R+1 | mur BBM 20 cm | mur BBM 20 cm 0.2 m | 2.86497 | 7.16242 | 7.16242 | 7.16242 | 0.572993 | 2.5 | 7.16242 | 1.43248 | 0.2 | 0.572993 | 7.16242 | 1.43248 | 7.16242
mur BBM 20 cm | 002 R+1 | mur BBM 20 cm | mur BBM 20 cm 0.2 m | 0.49 | 1.225 | 1.225 | 1.225 | 0.098 | 2.5 | 1.225 | 0.245 | 0.2 | 0.098 | 1.225 | 0.245 | 1.225
mur BBM 20 cm | 002 R+1 | mur BBM 20 cm | mur BBM 20 cm 0.2 m | 3.72246 | 9.30615 | 9.18062 | 2.73062 | 0.744492 | 2.5 | 9.05678 | 1.86123 | 0.2 | 0.744492 | 2.60678 | 0.57123 | 2.85615
voile BA 20 cm | 002 R+1 | voile BA 20 cm | voile BA 20 cm 0.2 m | 0.075 | 0.1875 | 0.1875 | 0.1875 | 0.015 | 2.5 | 0.1875 | 0.0375 | 0.2 | 0.015 | 0.1875 | 0.0375 | 0.1875
voile BA 20 cm | 002 R+1 | voile BA 20 cm | voile BA 20 cm 0.2 m | 0.49 | 1.225 | 1.475 | 1.475 | 0.098 | 2.5 | 0.975 | 0.245 | 0.2 | 0.098 | 0.975 | 0.245 | 1.225
mur BBM 20 cm | 002 R+1 | mur BBM 20 cm | mur BBM 20 cm 0.2 m | 3.54 | 8.85 | 8.85 | 8.85 | 0.708 | 2.5 | 8.85 | 1.77 | 0.2 | 0.708 | 8.85 | 1.77 | 8.85
mur BBM 20 cm | 002 R+1 | mur BBM 20 cm | mur BBM 20 cm 0.2 m | 4.28371 | 10.7093 | 10.7093 | 10.7093 | 0.856742 | 2.5 | 10.7093 | 2.14185 | 0.2 | 0.856742 | 10.7093 | 2.14185 | 10.7093
mur BBM 20 cm | 002 R+1 | mur BBM 20 cm | mur BBM 20 cm 0.2 m | 0.2 | 0.5 | 0.5 | 0.5 | 0.04 | 2.5 | 0.5 | 0.1 | 0.2 | 0.04 | 0.5 | 0.1 | 0.5
voile BA 20 cm | 002 R+1 | voile BA 20 cm | voile BA 20 cm 0.2 m | 0.2 | 0.5 | 0.5 | 0.5 | 0.04 | 2.5 | 0.5 | 0.1 | 0.2 | 0.04 | 0.5 | 0.1 | 0.5
voile BA 20 cm | 002 R+1 | voile BA 20 cm | voile BA 20 cm 0.2 m | 0.850177 | 2.12544 | 1.87544 | 1.87544 | 0.170035 | 2.5 | 2.37544 | 0.425088 | 0.2 | 0.170035 | 2.37544 | 0.425088 | 2.12544
mur BBM 20 cm | 002 R+1 | mur BBM 20 cm | mur BBM 20 cm 0.2 m | 0.000189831 | 0.000474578 | 0.000474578 | 0.000474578 | 0.0000379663 | 2.5 | 0.000474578 | 0.0000949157 | 0.2 | 0.0000379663 | 0.000474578 | 0.0000949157 | 0.000474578
voile BA 20 cm | 002 R+1 | voile BA 20 cm | voile BA 20 cm 0.2 m | 0.075 | 0.1875 | 0.4375 | 0.4375 | 0.015 | 2.5 | 0.0625 | 0.0375 | 0.2 | 0.015 | 0.0625 | 0.0375 | 0.1875
mur BBM 20 cm | 002 R+1 | mur BBM 20 cm | mur BBM 20 cm 0.2 m | 7.19502 | 17.9876 | 18.2382 | 18.2382 | 1.439 | 2.5 | 17.7369 | 3.59751 | 0.2 | 1.439 | 17.7369 | 3.59751 | 17.9876
mur BBM 20 cm | 002 R+1 | mur BBM 20 cm | mur BBM 20 cm 0.2 m | 6.44 | 16.1 | 15.85 | 12.88 | 1.288 | 2.5 | 16.1 | 3.22 | 0.2 | 1.288 | 13.13 | 2.626 | 13.13
voile BA 20 cm | 002 R+1 | voile BA 20 cm | voile BA 20 cm 0.2 m | 4.84004 | 12.1001 | 12.1001 | 12.1001 | 0.968009 | 2.5 | 12.1001 | 2.42002 | 0.2 | 0.968009 | 12.1001 | 2.42002 | 12.1001
voile BA 20 cm | 002 R+1 | voile BA 20 cm | voile BA 20 cm 0.2 m | 5.2 | 13 | 13 | 13 | 1.04 | 2.5 | 13 | 2.6 | 0.2 | 1.04 | 13 | 2.6 | 13
voile BA 20 cm | 002 R+1 | voile BA 20 cm | voile BA 20 cm 0.2 m | 0.159957 | 0.399892 | 0.399892 | 0.399892 | 0.0319913 | 2.5 | 0.399892 | 0.0799783 | 0.2 | 0.0319913 | 0.399892 | 0.0799783 | 0.399892
mur BBM 20 cm | 002 R+1 | mur BBM 20 cm | mur BBM 20 cm 0.2 m | 1.65743 | 4.14357 | 3.89357 | 2.85857 | 0.331485 | 2.5 | 4.14357 | 0.828713 | 0.2 | 0.331485 | 3.10857 | 0.621713 | 3.10857
voile BA 20 cm | 002 R+1 | voile BA 20 cm | voile BA 20 cm 0.2 m | 4.03 | 10.075 | 10.075 | 7.925 | 0.806 | 2.5 | 9.825 | 2.015 | 0.2 | 0.606 | 7.675 | 1.585 | 7.925
mur BBM 20 cm | 002 R+1 | mur BBM 20 cm | mur BBM 20 cm 0.2 m | 0.2 | 3.72775e-09 | 3.72775e-09 | 3.72775e-09 | 0.04 | 2.5 | 3.72775e-09 | 7.4555e-10 | 0.2 | 0.04 | 3.72775e-09 | 7.4555e-10 | 3.72775e-09
2 x PV BA 20 cm | 002 R+1 | PV BA 20 cm | PV BA 20 cm 0.2 m | 0.1 | 0.313 | 0.313 | 0.313 | 0.02 | 3.13 | 0.313 | 0.0626 | 0.2 | 0.02 | 0.313 | 0.0626 | 0.313
PV BA 20 cm | 002 R+1 | PV BA 20 cm | PV BA 20 cm 0.2 m | 3.44 | 10.7672 | 10.7672 | 9.2822 | 0.688 | 3.13 | 10.7672 | 2.15344 | 0.2 | 0.688 | 9.2822 | 1.85644 | 9.2822
PV BA 20 cm | 002 R+1 | PV BA 20 cm | PV BA 20 cm 0.2 m | 3.64 | 11.3932 | 11.3932 | 8.4232 | 0.728 | 3.13 | 11.3932 | 2.27864 | 0.2 | 0.728 | 8.4232 | 1.68464 | 8.4232
voile BA 20 cm | 002 R+1 | voile BA 20 cm | voile BA 20 cm 0.2 m | 0.125 | 0.3125 | 0.3125 | 0.3125 | 0.025 | 2.5 | 0.3125 | 0.0625 | 0.2 | 0.025 | 0.3125 | 0.0625 | 0.3125
mur BBM 15 cm | 003 R+2 | mur BBM 15 cm | mur BBM 15 cm 0.15 m | 1.425 | 1.92375 | 2.025 | 2.025 | 0.21375 | 1.35 | 1.8225 | 0.288563 | 0.15 | 0.21375 | 1.8225 | 0.288563 | 1.92375
mur BBM 15 cm | 003 R+2 | mur BBM 15 cm | mur BBM 15 cm 0.15 m | 7.195 | 9.71325 | 9.8145 | 9.8145 | 1.07925 | 1.35 | 9.612 | 1.45699 | 0.15 | 1.07925 | 9.612 | 1.45699 | 9.71325
mur BBM 15 cm | 003 R+2 | mur BBM 15 cm | mur BBM 15 cm 0.15 m | 1.60486 | 2.16656 | 2.26755 | 2.26755 | 0.240729 | 1.35 | 2.09257 | 0.324984 | 0.15 | 0.240729 | 2.09257 | 0.324984 | 2.16656
mur BBM 15 cm | 003 R+2 | mur BBM 15 cm | mur BBM 15 cm 0.15 m | 3.72744 | 5.03204 | 5.13303 | 5.13303 | 0.559116 | 1.35 | 4.93105 | 0.754806 | 0.15 | 0.559116 | 4.93105 | 0.754806 | 5.03204
mur BBM 15 cm | 003 R+2 | mur BBM 15 cm | mur BBM 15 cm 0.15 m | 4.86749 | 6.57111 | 6.68583 | 6.68583 | 0.730124 | 1.35 | 6.4564 | 0.985667 | 0.15 | 0.730124 | 6.4564 | 0.985667 | 6.57111
mur BBM 15 cm | 003 R+2 | mur BBM 15 cm | mur BBM 15 cm 0.15 m | 1.40657 | 1.89888 | 1.83644 | 1.83644 | 0.210986 | 1.35 | 2.01359 | 0.284831 | 0.15 | 0.210986 | 2.01359 | 0.284831 | 1.89888
mur BBM 20 cm | 003 R+2 | mur BBM 20 cm | mur BBM 20 cm 0.2 m | 0.0302341 | 0.0755851 | 0.145076 | 0.145076 | 0.00604681 | 2.5 | 0.0755851 | 0.015117 | 0.2 | 0.00604681 | 0.0755851 | 0.015117 | 0.0755851
mur BBM 20 cm | 003 R+2 | mur BBM 20 cm | mur BBM 20 cm 0.2 m | 2.94 | 7.35 | 7.35 | 3.05 | 0.588 | 2.5 | 6.85 | 1.47 | 0.2 | 0.588 | 2.55 | 0.61 | 3.05
mur BBM 20 cm | 003 R+2 | mur BBM 20 cm | mur BBM 20 cm 0.2 m | 0.0302341 | 0.0755851 | 0.0755851 | 0.0755851 | 0.00604681 | 2.5 | 0.207654 | 0.015117 | 0.2 | 0.00604681 | 0.207654 | 0.015117 | 0.0755851
mur BBM 20 cm | 003 R+2 | mur BBM 20 cm | mur BBM 20 cm 0.2 m | 4.47464 | 11.1866 | 10.6827 | 10.6827 | 0.894928 | 2.5 | 11.6905 | 2.23732 | 0.2 | 0.894928 | 11.6905 | 2.23732 | 11.1866
mur BBM 20 cm | 003 R+2 | mur BBM 20 cm | mur BBM 20 cm 0.2 m | 4.52986 | 11.3247 | 11.104 | 8.13399 | 0.905972 | 2.5 | 11.5453 | 2.26493 | 0.2 | 0.905972 | 8.57531 | 1.67093 | 8.35465
mur BBM 20 cm | 003 R+2 | mur BBM 20 cm | mur BBM 20 cm 0.2 m | 10.06 | 25.15 | 25.65 | 25.65 | 2.012 | 2.5 | 24.65 | 5.02999 | 0.2 | 2.012 | 24.65 | 5.02999 | 25.15
mur BBM 20 cm | 003 R+2 | mur BBM 20 cm | mur BBM 20 cm 0.2 m | 3.82686 | 9.56716 | 9.44152 | 5.44152 | 0.765373 | 2.5 | 9.31779 | 1.91343 | 0.2 | 0.765373 | 5.31779 | 1.11343 | 5.56716
voile BA 20 cm | 003 R+2 | voile BA 20 cm | voile BA 20 cm 0.2 m | 4.62 | 11.55 | 11.8 | 11.8 | 0.924 | 2.5 | 11.3 | 2.31 | 0.2 | 0.924 | 11.3 | 2.31 | 11.55
voile BA 20 cm | 003 R+2 | voile BA 20 cm | voile BA 20 cm 0.2 m | 0.26 | 0.65 | 0.9 | 0.9 | 0.052 | 2.5 | 0.4 | 0.13 | 0.2 | 0.052 | 0.4 | 0.13 | 0.65
voile BA 20 cm | 003 R+2 | voile BA 20 cm | voile BA 20 cm 0.2 m | 0.0879907 | 0.219977 | 0.0300232 | 0.0300232 | 0.0175981 | 2.5 | 0.469977 | 0.0439954 | 0.2 | 0.0175981 | 0.469977 | 0.0439954 | 0.219977
voile BA 20 cm | 003 R+2 | voile BA 20 cm | voile BA 20 cm 0.2 m | 5.6 | 14 | 14.25 | 14.25 | 1.12 | 2.5 | 13.75 | 2.8 | 0.2 | 1.12 | 13.75 | 2.8 | 14
mur BBM 20 cm | 003 R+2 | mur BBM 20 cm | mur BBM 20 cm 0.2 m | 3 | 7.5 | 7 | 5.965 | 0.6 | 2.5 | 7.5 | 1.5 | 0.2 | 0.6 | 6.465 | 1.293 | 6.465
voile BA 20 cm | 003 R+2 | voile BA 20 cm | voile BA 20 cm 0.2 m | 2.07996 | 5.19989 | 5.44989 | 3.29989 | 0.415991 | 2.5 | 4.94989 | 1.03998 | 0.2 | 0.215991 | 2.79989 | 0.609978 | 3.04989
voile BA 20 cm | 003 R+2 | voile BA 20 cm | voile BA 20 cm 0.2 m | 4.94004 | 12.3501 | 12.3501 | 10.2001 | 0.988009 | 2.5 | 12.3501 | 2.47002 | 0.2 | 0.788009 | 10.2001 | 2.04002 | 10.2001
mur BBM 20 cm | 003 R+2 | mur BBM 20 cm | mur BBM 20 cm 0.2 m | 4.9529 | 12.3822 | 12.1322 | 9.16224 | 0.990579 | 2.5 | 12.3822 | 2.47645 | 0.2 | 0.990579 | 9.41224 | 1.88245 | 9.41224
voile BA 20 cm | 003 R+2 | voile BA 20 cm | voile BA 20 cm 0.2 m | 2.35 | 5.875 | 5.875 | 5.875 | 0.47 | 2.5 | 5.625 | 1.175 | 0.2 | 0.47 | 5.625 | 1.175 | 5.875
voile BA 20 cm | 003 R+2 | voile BA 20 cm | voile BA 20 cm 0.2 m | 1.32 | 3.3 | 3.05 | 0.9 | 0.264 | 2.5 | 3.55 | 0.66 | 0.2 | 0.064 | 1.4 | 0.23 | 1.15
voile BA 20 cm | 003 R+2 | voile BA 20 cm | voile BA 20 cm 0.2 m | 4.03 | 10.075 | 10.075 | 7.925 | 0.806 | 2.5 | 9.825 | 2.015 | 0.2 | 0.606 | 7.675 | 1.585 | 7.925
voile BA 20 cm | 003 R+2 | voile BA 20 cm | voile BA 20 cm 0.2 m | 0.6 | 1.5 | 1.75 | 1.75 | 0.12 | 2.5 | 1.25 | 0.3 | 0.2 | 0.12 | 1.25 | 0.3 | 1.5
voile BA 20 cm | 003 R+2 | voile BA 20 cm | voile BA 20 cm 0.2 m | 2.20064 | 5.50161 | 5.25161 | 5.25161 | 0.440129 | 2.5 | 5.50161 | 1.10032 | 0.2 | 0.440129 | 5.50161 | 1.10032 | 5.50161
voile BA 20 cm | 003 R+2 | voile BA 20 cm | voile BA 20 cm 0.2 m | 1.09 | 2.725 | 2.975 | 2.975 | 0.218 | 2.5 | 2.475 | 0.545 | 0.2 | 0.218 | 2.475 | 0.545 | 2.725
voile BA 20 cm | 003 R+2 | voile BA 20 cm | voile BA 20 cm 0.2 m | 0.59 | 1.475 | 1.725 | 1.725 | 0.118 | 2.5 | 1.225 | 0.295 | 0.2 | 0.118 | 1.225 | 0.295 | 1.475
voile BA 20 cm | 003 R+2 | voile BA 20 cm | voile BA 20 cm 0.2 m | 0.6 | 1.5 | 1.25 | 1.25 | 0.12 | 2.5 | 1.75 | 0.3 | 0.2 | 0.12 | 1.75 | 0.3 | 1.5
voile BA 20 cm | 003 R+2 | voile BA 20 cm | voile BA 20 cm 0.2 m | 1.68 | 4.2 | 3.7 | 3.7 | 0.336 | 2.5 | 4.2 | 0.84 | 0.2 | 0.336 | 4.2 | 0.84 | 4.2
mur BBM 20 cm | 003 R+2 | mur BBM 20 cm | mur BBM 20 cm 0.2 m | 4.67146 | 11.6787 | 11.584 | 5.58398 | 0.934293 | 2.5 | 11.3954 | 2.33573 | 0.2 | 0.934293 | 5.39541 | 1.13573 | 5.67866
mur BBM 20 cm | 003 R+2 | mur BBM 20 cm | mur BBM 20 cm 0.2 m | 4.41438 | 11.036 | 10.532 | 9.04704 | 0.882876 | 2.5 | 11.5399 | 2.20719 | 0.2 | 0.882876 | 10.0549 | 1.91019 | 9.55095
mur BBM 20 cm | 003 R+2 | mur BBM 20 cm | mur BBM 20 cm 0.2 m | 2.79064 | 6.97661 | 6.97661 | 4.97661 | 0.558129 | 2.5 | 6.97661 | 1.39532 | 0.2 | 0.558129 | 4.97661 | 0.995322 | 4.97661
mur BBM 20 cm | 003 R+2 | mur BBM 20 cm | mur BBM 20 cm 0.2 m | 1.22809 | 3.07022 | 2.88272 | 2.88272 | 0.245618 | 2.5 | 3.07022 | 0.614044 | 0.2 | 0.245618 | 3.07022 | 0.614044 | 3.07022
mur BBM 20 cm | 003 R+2 | mur BBM 20 cm | mur BBM 20 cm 0.2 m | 3.85257 | 9.63142 | 9.38079 | 7.89579 | 0.770514 | 2.5 | 9.88206 | 1.92628 | 0.2 | 0.770514 | 8.39706 | 1.62928 | 8.14642
mur BBM 20 cm | 003 R+2 | mur BBM 20 cm | mur BBM 20 cm 0.2 m | 6.43973 | 16.0993 | 15.8493 | 12.8793 | 1.28795 | 2.5 | 16.0993 | 3.21986 | 0.2 | 1.28795 | 13.1293 | 2.62586 | 13.1293
voile BA 20 cm | 003 R+2 | voile BA 20 cm | voile BA 20 cm 0.2 m | 1.39201 | 3.48002 | 3.23002 | 3.23002 | 0.278402 | 2.5 | 3.48002 | 0.696005 | 0.2 | 0.278402 | 3.48002 | 0.696005 | 3.48002
voile BA 20 cm | 003 R+2 | voile BA 20 cm | voile BA 20 cm 0.2 m | 1.42 | 3.55 | 3.3 | 3.3 | 0.284 | 2.5 | 3.8 | 0.71 | 0.2 | 0.284 | 3.8 | 0.71 | 3.55
voile BA 20 cm | 003 R+2 | voile BA 20 cm | voile BA 20 cm 0.2 m | 0.799355 | 1.99839 | 2.24839 | 2.24839 | 0.159871 | 2.5 | 1.74839 | 0.399678 | 0.2 | 0.159871 | 1.74839 | 0.399678 | 1.99839
mur BBM 20 cm | 003 R+2 | mur BBM 20 cm | mur BBM 20 cm 0.2 m | 4.52436 | 11.3109 | 11.1234 | 5.63839 | 0.904871 | 2.5 | 11.3109 | 2.26218 | 0.2 | 0.904871 | 5.82589 | 1.16518 | 5.82589
mur BBM 20 cm | 003 R+2 | mur BBM 20 cm | mur BBM 20 cm 0.2 m | 1.63301 | 4.08253 | 4.33253 | 4.33253 | 0.326602 | 2.5 | 3.54929 | 0.816506 | 0.2 | 0.326602 | 3.54929 | 0.816506 | 4.08253
mur BBM 20 cm | 003 R+2 | mur BBM 20 cm | mur BBM 20 cm 0.2 m | 1.26505 | 3.16263 | 2.69197 | 1.37197 | 0.25301 | 2.5 | 3.41263 | 0.632526 | 0.2 | 0.25301 | 2.09263 | 0.368526 | 1.84263
mur BBM 20 cm | 003 R+2 | mur BBM 20 cm | mur BBM 20 cm 0.2 m | 2.76138 | 2.07103 | 2.07103 | 2.07103 | 0.552275 | 0.75 | 2.07103 | 0.414206 | 0.2 | 0.552275 | 2.07103 | 0.414206 | 2.07103
2 x PV BA 20 cm | 003 R+2 | PV BA 20 cm | PV BA 20 cm 0.2 m | 0.1 | 0.27 | 0.27 | 0.27 | 0.02 | 2.7 | 0.27 | 0.054 | 0.2 | 0.02 | 0.27 | 0.054 | 0.27
PV BA 20 cm | 003 R+2 | PV BA 20 cm | PV BA 20 cm 0.2 m | 7.08 | 19.116 | 19.116 | 14.661 | 1.416 | 2.7 | 19.116 | 3.8232 | 0.2 | 1.416 | 14.661 | 2.9322 | 14.661
acrotère Blocs à bancher 20 cm | 004 Toiture Terrasse | acrotère Blocs à bancher 20 cm | acrotère Blocs à bancher 20 cm 0.2 m | 22.7751 | 28.4688 | 28.2332 | 28.2332 | 4.55501 | 1.25 | 28.7045 | 5.69376 | 0.2 | 4.55501 | 28.7045 | 5.69376 | 28.4688
acrotère Blocs à bancher 20 cm | 004 Toiture Terrasse | acrotère Blocs à bancher 20 cm | acrotère Blocs à bancher 20 cm 0.2 m | 10.06 | 12.575 | 12.825 | 12.825 | 2.012 | 1.25 | 12.325 | 2.515 | 0.2 | 2.012 | 12.325 | 2.515 | 12.575
acrotère Blocs à bancher 20 cm | 004 Toiture Terrasse | acrotère Blocs à bancher 20 cm | acrotère Blocs à bancher 20 cm 0.2 m | 3.82681 | 4.78352 | 4.7832 | 4.7832 | 0.765363 | 1.25 | 4.78384 | 0.956704 | 0.2 | 0.765363 | 4.78384 | 0.956704 | 4.78352
acrotère Blocs à bancher 20 cm | 004 Toiture Terrasse | acrotère Blocs à bancher 20 cm | acrotère Blocs à bancher 20 cm 0.2 m | 1.70004 | 2.12505 | 2.12505 | 2.12505 | 0.340009 | 1.25 | 2.12505 | 0.425011 | 0.2 | 0.340009 | 2.12505 | 0.425011 | 2.12505
acrotère Blocs à bancher 20 cm | 004 Toiture Terrasse | acrotère Blocs à bancher 20 cm | acrotère Blocs à bancher 20 cm 0.2 m | 8.54309 | 10.6789 | 10.6789 | 10.6789 | 1.70862 | 1.25 | 10.6789 | 2.13577 | 0.2 | 1.70862 | 10.6789 | 2.13577 | 10.6789
2 x acrotère Blocs à bancher 20 cm | 004 Toiture Terrasse | acrotère Blocs à bancher 20 cm | acrotère Blocs à bancher 20 cm 0.2 m | 2.965 | 3.70625 | 3.70625 | 3.70625 | 0.593 | 1.25 | 3.70625 | 0.74125 | 0.2 | 0.593 | 3.70625 | 0.74125 | 3.70625
acrotère Blocs à bancher 20 cm | 004 Toiture Terrasse | acrotère Blocs à bancher 20 cm | acrotère Blocs à bancher 20 cm 0.2 m | 7.08 | 8.85 | 9.1 | 9.1 | 1.416 | 1.25 | 8.6 | 1.77 | 0.2 | 1.416 | 8.6 | 1.77 | 8.85
acrotère Blocs à bancher 20 cm | 004 Toiture Terrasse | acrotère Blocs à bancher 20 cm | acrotère Blocs à bancher 20 cm 0.2 m | 4.77143 | 5.96429 | 5.98091 | 5.98091 | 0.954287 | 1.25 | 5.94767 | 1.19286 | 0.2 | 0.954287 | 5.94767 | 1.19286 | 5.96429
acrotère Blocs à bancher 20 cm | 004 Toiture Terrasse | acrotère Blocs à bancher 20 cm | acrotère Blocs à bancher 20 cm 0.2 m | 11.8517 | 14.8147 | 14.5627 | 14.5627 | 2.37035 | 1.25 | 15.0666 | 2.96294 | 0.2 | 2.37035 | 15.0666 | 2.96294 | 14.8147

# IfcWindow (48)
Description: Fenêtre
Name | In | OverallHeight (m) | OverallWidth (m)
5 x BL 300 x 115 | 001 RdC | 1.15 | 3
BL 200 x 115 | 001 RdC | 1.15 | 2
4 x BL 90 x 115 | 001 RdC | 1.15 | 0.9
BL 90 x 195 | 001 RdC | 1.95 | 0.9
BL 300 x 215 | 001 RdC | 2.15 | 3
10 x BL 90 x 165 | 002 R+1 | 1.65 | 0.9
3 x BL 300 x 215 | 002 R+1 | 2.15 | 3
BL 80 x 165 | 002 R+1 | 1.65 | 0.8
BL 200 x 215 | 002 R+1 | 2.15 | 2
BL 90 x 115 | 002 R+1 | 1.15 | 0.9
BL 100 x 215 | 002 R+1 | 2.15 | 1
12 x BL 90 x 165 | 003 R+2 | 1.65 | 0.9
BL 300 x 215 | 003 R+2 | 2 | 3
2 x BL 200 x 200 | 003 R+2 | 2 | 2
BL 100 x 200 | 003 R+2 | 2 | 1
BL 80 x 165 | 003 R+2 | 1.65 | 0.8
BL 200 x 215 | 003 R+2 | 2.15 | 2
BL 90 x 115 | 003 R+2 | 1.15 | 0.9
